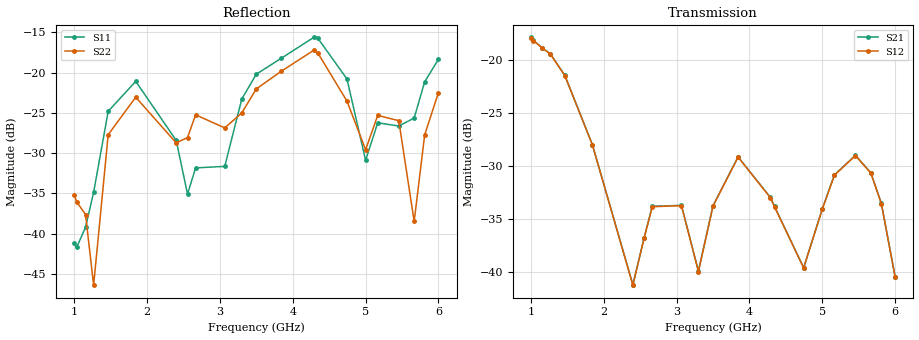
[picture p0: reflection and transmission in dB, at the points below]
!Agilent Technologies,E8364B,MY43040528,A.07.50.67
!Agilent E8364B: A.07.50.67
!Date: Sunday, March 01, 2026 21:29:54
!Correction: S11(Full 2 Port(1,2))
!S21(Full 2 Port(1,2))
!S12(Full 2 Port(1,2))
!S22(Full 2 Port(1,2))
!S2P File: Measurements: S11, S21, S12, S22:
# Hz S  dB  R 50
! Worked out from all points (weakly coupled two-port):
!   451 points, 1 GHz to 6 GHz, reference 50 ohm
!   highest |S21| = -17.90 dB at 1 GHz (marker M1); lowest = -41.2 dB at 2.4 GHz (marker M2)
!   lowest |S11| = -41.7 dB at 1.033 GHz (marker M3), VSWR 1.02, Z = 49.9 + j0.809 ohm
!   |S11| at or under -10 dB: start of sweep to end of sweep
!   |S22| runs from -46.5 to -17.0 dB; largest |S21 - S12| = 0.00046
!   S11 on the Smith chart (normalised r, x): 1 GHz: 1.00, +0.02; 4.289 GHz: 1.25, -0.28; 6 GHz: 0.98, -0.24
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1e9  -41.14 78.0  -17.90 25.9  -17.94 25.9  -35.14 15.0
1.033333e9  -41.70 99.5  -18.17 15.9  -18.20 16.0  -36.03 16.4
1.155556e9  -39.20 137.1  -18.88 -20.6  -18.90 -20.6  -37.61 17.4
1.266667e9  -34.85 170.4  -19.44 -56.7  -19.47 -56.6  -46.38 78.9
1.466667e9  -24.79 155.2  -21.49 -124.9  -21.51 -124.9  -27.69 86.7
1.844444e9  -21.07 87.2  -28.01 114.6  -28.03 114.6  -23.04 -2.3
2.4e9  -28.40 15.2  -41.21 -129.6  -41.25 -129.7  -28.71 -67.9
2.555556e9  -35.07 39.9  -36.77 117.8  -36.80 117.9  -28.05 -52.8
2.666667e9  -31.82 69.5  -33.82 62.2  -33.86 62.2  -25.23 -58.9
3.066667e9  -31.63 70.3  -33.73 -100.3  -33.76 -100.3  -26.85 -116.6
3.3e9  -23.27 79.1  -39.92 -136.4  -39.97 -136.3  -24.99 -98.5
3.5e9  -20.18 50.5  -33.77 -159.6  -33.80 -159.5  -22.01 -122.6
3.844444e9  -18.19 18.9  -29.16 73.7  -29.19 73.8  -19.80 -153.5
4.288889e9  -15.61 -41.8  -32.99 -91.6  -33.02 -91.6  -17.21 125.4
4.344444e9  -15.72 -50.5  -33.83 -111.6  -33.87 -111.6  -17.55 114.0
4.744444e9  -20.78 -110.1  -39.61 56.3  -39.63 56.4  -23.53 34.3
5e9  -30.87 -94.3  -34.07 -95.3  -34.10 -95.2  -29.56 42.2
5.166667e9  -26.22 -66.4  -30.86 -173.9  -30.90 -173.9  -25.30 32.5
5.455556e9  -26.62 -91.9  -29.01 59.1  -29.04 59.2  -25.96 -37.1
5.666667e9  -25.63 -56.7  -30.66 -30.9  -30.69 -30.8  -38.47 -13.8
5.811111e9  -21.12 -63.6  -33.54 -89.3  -33.58 -89.3  -27.71 18.9
6e9  -18.33 -88.4  -40.46 -151.5  -40.50 -151.5  -22.47 -14.0
